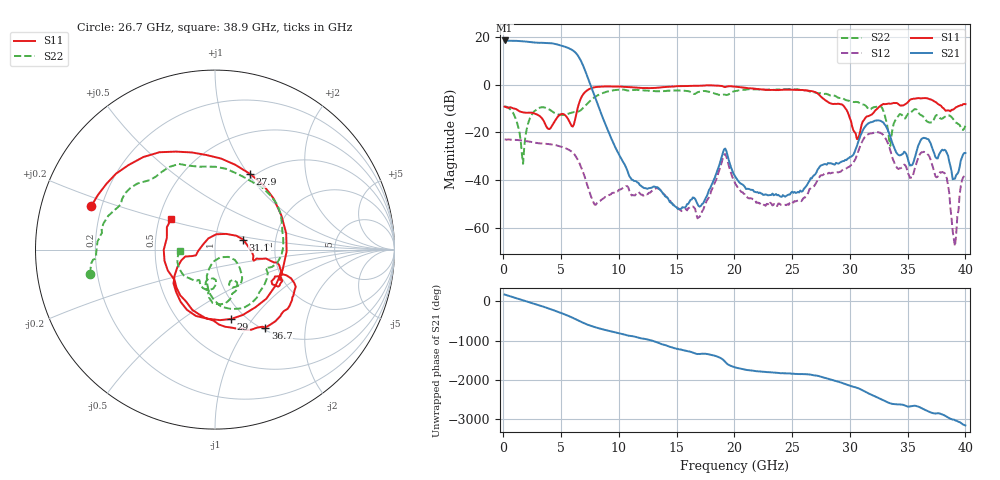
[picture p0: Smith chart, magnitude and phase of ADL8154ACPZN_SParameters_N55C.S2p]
! Analog Devices, Inc."
! Device:	ADL8154ACPZN
! Description:	"10 MHz to 6 GHz, Wideband, Low Noise Amplifier"
! Conditions:	Vdd = 5.0 V
!		IDQ = 125 mA
!		Pin = -25 dBm
!		Operating Temperature = -55 C (at package bottom)
! Product validation unit SN30 soldered down to Evaluation Board as shown on ADL8154-EVALZ User Guide. Board loss de-embedded from S21 magnitude.  All other RF measurements reference to RF coaxial connector.
! Frequency (GHz)	S11_Mag (dB)	S11_Phase (deg)	S21_Mag (dB)	S21_Phase (deg)	S12_Mag (dB)	S12_Phase (deg)	S22_Mag (dB)	S22_Phase (deg)
#  GHZ  S  DB  R 50
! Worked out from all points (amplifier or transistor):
!   400 points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, 110 MHz to 40 GHz, reference 50 ohm
!   highest |S21| = 18.5 dB at 110 MHz (marker M1)
!   |S21| within 3 dB of that: start of sweep to 5.54 GHz
!   unconditionally stable (mu >= 1): start of sweep to end of sweep
!   at 6.708 GHz: K = 5.39, MAG = 11.9 dB, |S12| = -34.3 dB
!   at 20.11 GHz: K = 445.57, MAG = -28.0 dB, |S12| = -41.6 dB
!   at 40 GHz: K = 894.81, MAG = -27.8 dB, |S12| = -38.0 dB
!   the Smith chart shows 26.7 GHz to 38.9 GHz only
!   S11 on the Smith chart (normalised r, x): 26.7 GHz: 0.16, +0.17; 27.9 GHz: 0.95, +1.02; 29 GHz: 0.86, -0.79; 31.1 GHz: 1.36, +0.16; 36.7 GHz: 1.04, -1.23; 38.9 GHz: 0.58, +0.22
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0.11  -9.23 -178.9  18.46 170.9  -22.97 -5.4  -9.12 169.7
1.01  -10.10 138.2  18.32 88.8  -23.13 -72.4  -13.56 92.2
1.91  -11.77 109.9  17.99 6.4  -23.61 -140.3  -21.68 -138.0
2.309  -11.76 95.6  17.80 -30.1  -23.91 -170.8  -13.97 -179.2
2.909  -12.50 56.4  17.54 -85.0  -24.47 143.3  -10.15 137.4
3.809  -18.17 -55.0  17.42 -171.8  -24.86 71.6  -10.05 74.3
4.609  -14.13 153.6  16.86 104.1  -25.44 2.5  -12.27 15.6
5.409  -13.11 62.8  15.69 14.5  -26.66 -70.8  -12.57 -64.9
6.108  -16.63 -93.8  13.96 -74.2  -28.94 -146.4  -11.49 -142.8
6.808  -4.86 136.8  9.00 -173.6  -35.49 127.1  -10.28 162.2
7.908  -1.12 44.6  -4.95 63.8  -50.23 -16.7  -5.28 77.9
13.407  -1.31 177.5  -43.14 25.3  -43.62 24.2  -2.82 174.5
20.105  -0.88 14.4  -38.71 115.5  -41.64 117.8  -2.71 -4.4
26.703  -2.72 160.8  -39.24 -72.3  -43.01 -75.5  -2.98 -169.0
26.803  -2.85 155.0  -38.38 -80.3  -42.73 -82.0  -3.10 -171.8
27.903  -6.66 65.0  -33.29 -151.6  -37.45 -154.0  -3.85 169.6
29.003  -8.03 -76.8  -33.11 117.2  -36.74 111.9  -5.52 132.9
31.102  -15.56 19.7  -19.31 -104.5  -23.47 -104.2  -8.29 8.8
33.402  -7.95 -23.3  -20.43 -65.3  -25.92 -64.5  -23.27 -99.2
36.701  -5.72 -57.1  -22.79 93.6  -29.06 94.5  -15.50 -102.7
38.9  -10.53 145.1  -39.63 -131.0  -61.36 -90.9  -14.15 -178.1
40  -8.18 63.3  -28.64 82.4  -38.01 60.7  -17.28 151.5
